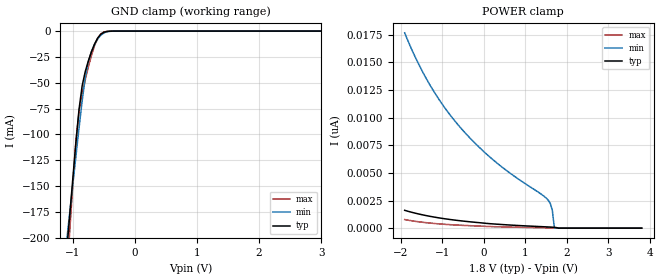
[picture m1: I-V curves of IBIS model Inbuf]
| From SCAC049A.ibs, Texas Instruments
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|=================== Models Section ----------------------------------------
[Model]   Inbuf
Model_type   Input
|Signals   FBIN, FBIN-
Vinh = 1.105
Vinl = 0.665
|   typ   min   max
C_comp   2.27pF   NA   NA
|   typ   min   max
[Temperature Range]   40   105   0
[Voltage range]   1.8   1.7   1.9
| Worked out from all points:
|   GND clamp passes 1 mA (typ) near -0.49 V on its own axis
[Power Clamp]
|   Voltage   I(typ)   I(min)   I(max)
-1.9V     1.614nA    17.66nA    777.8pA
-1.65V    1.359nA    15.5nA     621.1pA
-1.4V     1.15nA     13.66nA    502.3pA
-1.1V     945pA      11.79nA    395.1pA
-800mV    779.2pA    10.2nA     314.7pA
-350mV    583.1pA    8.23nA     226.7pA
150mV     405.5pA    6.425nA    145.3pA
1.55V     108.6pA    2.536nA    27.33pA
1.6V      98.97pA    2.251nA    23.94pA
1.65V     88.21pA    1.612nA    20.54pA
1.7V      74.62pA    0A         17.08pA
3.8V      0A         0A         0A
[GND Clamp]
|   Voltage   I(typ)   I(min)   I(max)
-1.9V     -785mA     -642.5mA   -982.6mA
-1.1V     -213.5mA   -203mA     -239.7mA
-1.05V    -177.8mA   -175.5mA   -193.4mA
-950mV    -107.2mA   -120.7mA   -105.8mA
-900mV    -75.44mA   -93.5mA    -77.36mA
-850mV    -52.8mA    -67.41mA   -60.58mA
-800mV    -39.08mA   -44.92mA   -47.05mA
-750mV    -28.78mA   -29.34mA   -34.65mA
-700mV    -19.93mA   -19.64mA   -23.44mA
-600mV    -6.705mA   -7.641mA   -6.925mA
-500mV    -1.106mA   -1.771mA   -891.8uA
3.8V      0A         0A         0A
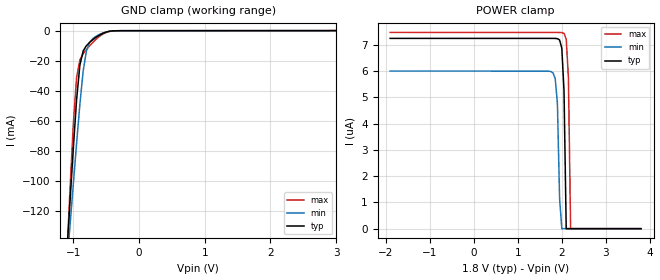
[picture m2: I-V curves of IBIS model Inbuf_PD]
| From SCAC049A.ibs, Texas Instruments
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[Model]   Inbuf_PD
Model_type   Input
|Signals   CK, CK-
Vinh = 1.105
Vinl = 0.665
|   typ   min   max
C_comp   2.27pF   NA   NA
|   typ   min   max
[Temperature Range]   40   105   0
[Voltage range]   1.8   1.7   1.9
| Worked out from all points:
|   GND clamp passes 1 mA (typ) near -0.51 V on its own axis
[Power Clamp]
|   Voltage   I(typ)   I(min)   I(max)
-1.9V     7.24uA     5.997uA    7.467uA
1.65V     7.239uA    5.993uA    7.464uA
1.8V      7.239uA    5.93uA     7.464uA
1.85V     7.238uA    5.706uA    7.464uA
1.9V      7.229uA    4.763uA    7.464uA
1.95V     7.177uA    1.126uA    7.464uA
2V        6.868uA    0A         7.46uA
2.05V     5.24uA     0A         7.431uA
2.1V      0A         0A         7.209uA
2.15V     0A         0A         5.74uA
2.2V      0A         0A         0A
3.8V      0A         0A         0A
[GND Clamp]
|   Voltage   I(typ)   I(min)   I(max)
-1.9V     -720.8mA   -596.7mA   -894.6mA
-1.1V     -149.4mA   -157.1mA   -151.8mA
-1.05V    -113.7mA   -129.6mA   -105.8mA
-1V       -78.56mA   -102.2mA   -62.2mA
-950mV    -45.96mA   -75.1mA    -31.1mA
-900mV    -23mA      -49.04mA   -19.51mA
-850mV    -13.5mA    -26.93mA   -15.37mA
-800mV    -9.939mA   -13.33mA   -12.53mA
-750mV    -7.724mA   -7.582mA   -9.985mA
-650mV    -4.237mA   -3.627mA   -5.552mA
-350mV    -43.85uA   -61.05uA   -51.55uA
3.8V      61.13uA    41.39uA    81.04uA
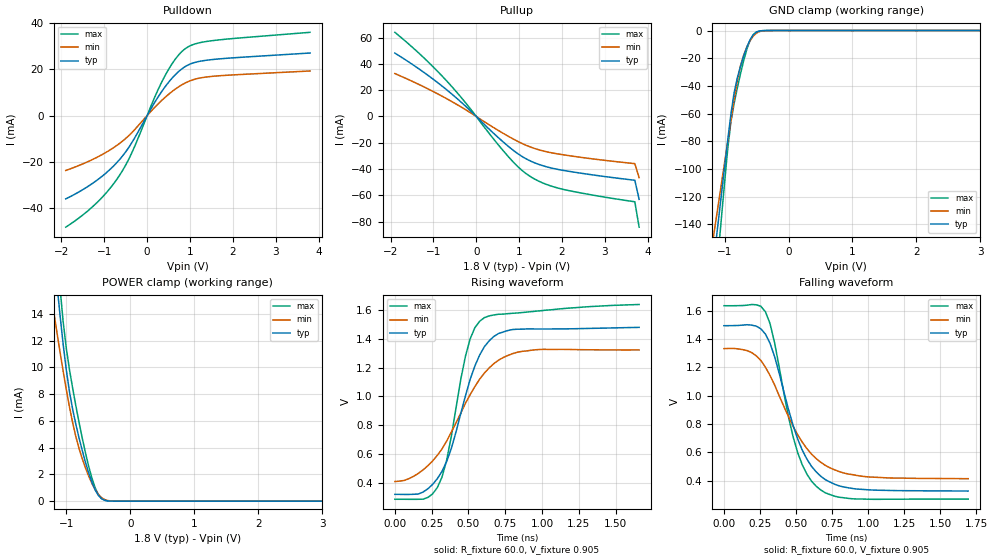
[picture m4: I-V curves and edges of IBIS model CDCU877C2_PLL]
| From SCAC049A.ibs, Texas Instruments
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[Model]   CDCU877C2_PLL
Model_type   Output
Vmeas =   0.905V
Cref  =   10pF
Rref  =   60.000Ohm   |Diff Termination 120ohm, or 60 ohms to Vref
Vref  =   0.905V
|   typ   min   max
C_comp   1.44pF   1.38pF   1.64pF
[Model Spec]
|  subparameter   typ   min   max
Vmeas   0.905V   0.869V   0.970V
|   typ   min   max
[Temperature Range]   40   105   0
[Voltage Range]   1.8V   1.7V   1.9V
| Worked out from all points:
|   slope of the pulldown table from 0 to 0.27 V, typ, clamps not added: 31.9 ohm
|   slope of the pullup table from 0 to 0.27 V, typ, clamps not added: 31.2 ohm
|   GND clamp passes 1 mA (typ) near -0.49 V on its own axis
|   POWER clamp passes 1 mA (typ) near -0.56 V on its own axis
|   rising waveform, R_fixture 60.0, V_fixture 0.905: 20-80 % time 206ps typ, 302ps min, 151ps max; typ from 0.318 V to 1.48 V
|   falling waveform, R_fixture 60.0, V_fixture 0.905: 20-80 % time 216ps typ, 283ps min, 179ps max; typ from 1.49 V to 0.327 V
[Pullup]
|  Voltage   I(typ)   I(min)   I(max)
-1.9V     48.29mA    32.72mA    64.12mA
-1.3V     35.4mA     23.8mA     47.06mA
-700mV    20.6mA     13.72mA    27.43mA
-250mV    7.853mA    5.187mA    10.47mA
650mV     -19.99mA   -13.24mA   -26.86mA
900mV     -26.67mA   -17.8mA    -35.92mA
1.1V      -31.07mA   -21.03mA   -41.92mA
1.45V     -36.38mA   -25.26mA   -49.13mA
1.9V      -40.28mA   -28.49mA   -54.45mA
2.65V     -44.18mA   -32.01mA   -59.47mA
3.7V      -48.56mA   -35.91mA   -64.96mA
3.8V      -63.12mA   -46.61mA   -84.29mA
[Pulldown]
|  Voltage   I(typ)   I(min)   I(max)
-1.9V     -36.13mA   -23.8mA    -48.38mA
-1.2V     -28.42mA   -18.37mA   -38.25mA
-900mV    -23.92mA   -15.3mA    -32.31mA
-650mV    -19.19mA   -12.15mA   -26.05mA
-300mV    -9.972mA   -6.288mA   -13.75mA
150mV     4.889mA    3.039mA    6.847mA
350mV     10.68mA    6.735mA    14.89mA
600mV     16.6mA     10.69mA    22.96mA
850mV     20.78mA    13.74mA    28.41mA
1.1V      22.95mA    15.68mA    30.94mA
1.45V     24.13mA    16.85mA    32.29mA
3.8V      27.11mA    19.32mA    36.07mA
[Power Clamp]
|  Voltage   I(typ)   I(min)   I(max)
-1.9V     58.12mA    37.62mA    76.79mA
-1.25V    21.57mA    15.87mA    26.04mA
-1.2V     18.95mA    14.29mA    22.48mA
-1.15V    16.41mA    12.73mA    19.12mA
-1.1V     14mA       11.21mA    16.05mA
-1.05V    11.76mA    9.736mA    13.45mA
-1V       9.796mA    8.335mA    11.42mA
-850mV    5.728mA    4.811mA    7.113mA
-700mV    2.896mA    2.478mA    3.596mA
-600mV    1.41mA     1.328mA    1.719mA
-450mV    184.6uA    259.8uA    195.6uA
3.8V      0A         0A         0A
[GND Clamp]
|  Voltage   I(typ)   I(min)   I(max)
-1.9V     -459mA     -372.7mA   -578.2mA
-1.2V     -179mA     -157.3mA   -214.2mA
-1.15V    -159mA     -141.9mA   -188.2mA
-1.1V     -139mA     -126.6mA   -162.2mA
-1.05V    -119.1mA   -111.2mA   -136.2mA
-950mV    -79.26mA   -80.43mA   -85.57mA
-900mV    -60.36mA   -65.13mA   -65.9mA
-850mV    -44.95mA   -50.14mA   -52.69mA
-700mV    -18.31mA   -17.68mA   -21.67mA
-600mV    -6.591mA   -7.327mA   -6.935mA
-500mV    -1.17mA    -1.81mA    -976.7uA
3.8V      0A         0A         0A
[Ramp]
|   typ   min   max
|dV/dt_r   0.7054/6.5305E-11   0.5547/9.5372E-11   0.7967/4.6725E-11
|dV/dt_f   0.7054/6.8631E-11   0.5547/8.9905E-11   0.7967/5.2828E-11
dV/dt_r   0.7054/2.0895E-10   0.5547/3.0534E-10   0.7967/1.4784E-10
dV/dt_f   0.7054/2.1966E-10   0.5547/2.8713E-10   0.7967/1.6919E-10
R_load = 152ohms  |120ohms + 1x channel impedance (HIGH+LOW)/2= 31.85ohms
| R_load = differential termination 120ohm channel to channel,
|   or single-ended with Rload to common mode voltage.
[Rising Waveform]
R_fixture = 60.0   | 1/2 of differential resistor
V_fixture = 0.905   | common mode voltage NOM
V_fixture_min = 0.869   | common mode voltage WEAK
V_fixture_max = 0.970   | common mode voltage STRONG
|   time   V(typ)   V(min)   V(max)
0s        317.6mV    407mV      283.3mV
160ps     319.9mV    464.1mV    283.1mV
288ps     426mV      588.3mV    363.7mV
352ps     546.5mV    688.7mV    555.4mV
480ps     1.005V     953.1mV    1.282V
512ps     1.12V      1.013V     1.403V
576ps     1.288V     1.12V      1.524V
704ps     1.439V     1.253V     1.573V
864ps     1.469V     1.315V     1.585V
1.66ns    1.482V     1.324V     1.641V
[Falling Waveform]
R_fixture = 60.0   | 1/2 of differential resistor
V_fixture = 0.905   | common mode voltage NOM
V_fixture_min = 0.869   | common mode voltage WEAK
V_fixture_max = 0.970   | common mode voltage STRONG
|   time   V(typ)   V(min)   V(max)
0s        1.493V     1.331V     1.634V
192ps     1.497V     1.304V     1.643V
288ps     1.434V     1.201V     1.591V
352ps     1.274V     1.075V     1.371V
448ps     903mV      853.1mV    850.1mV
512ps     694.4mV    724mV      598mV
576ps     552.7mV    626.1mV    446.6mV
672ps     431.9mV    530.3mV    335mV
960ps     339.2mV    431.6mV    271.2mV
1.696ns   327.4mV    414.6mV    270.4mV
